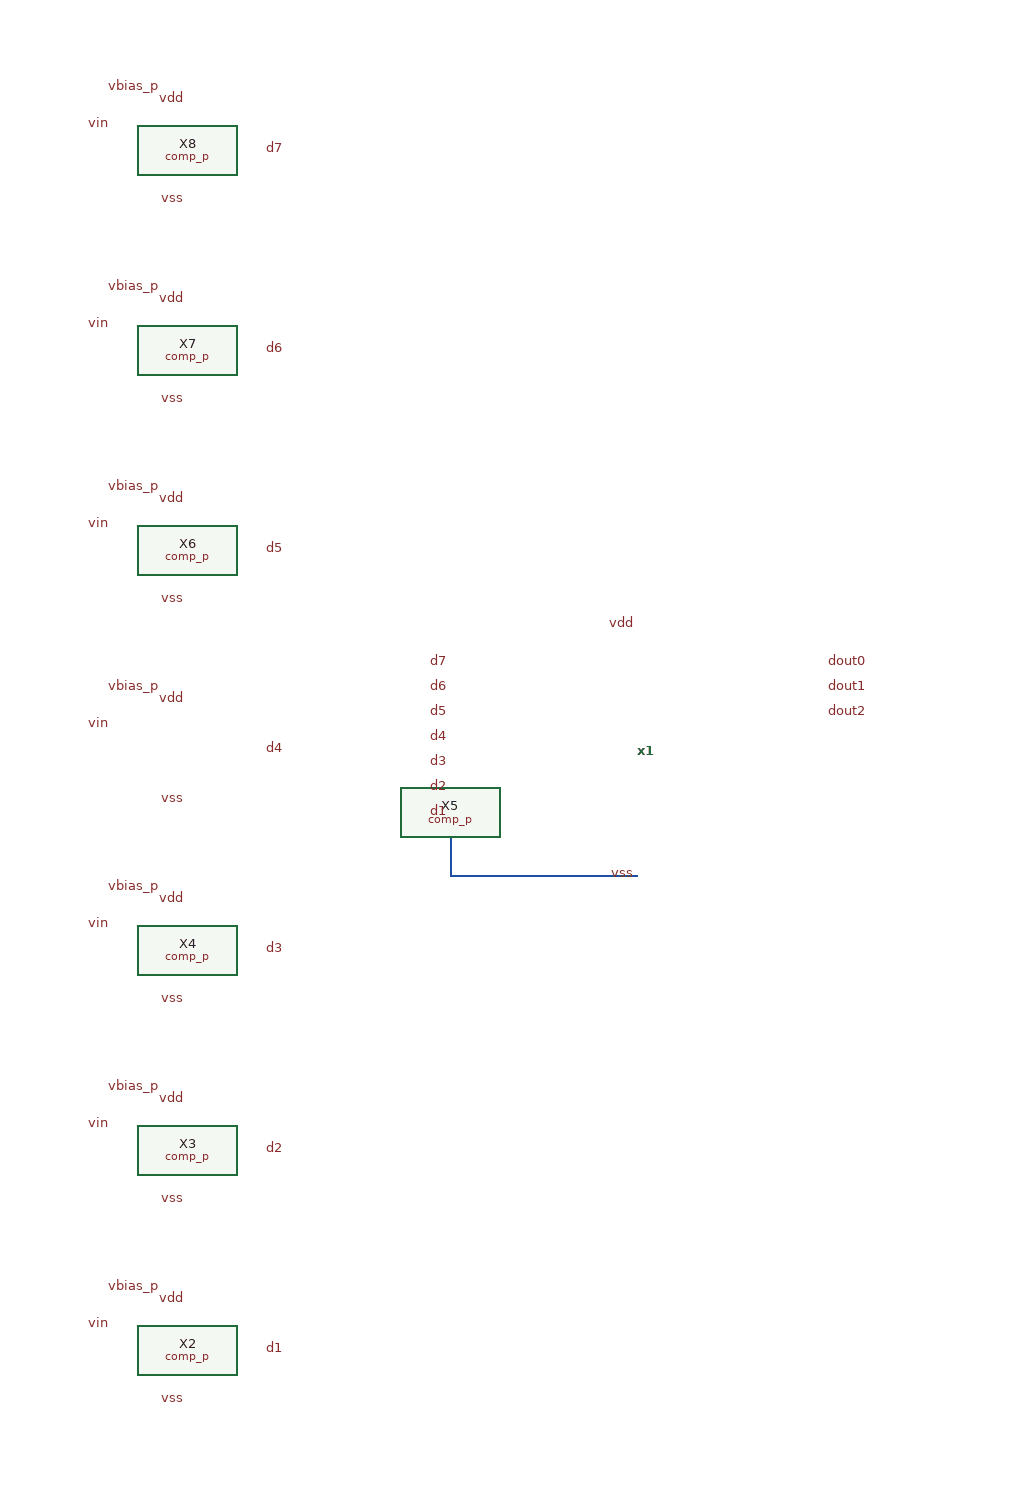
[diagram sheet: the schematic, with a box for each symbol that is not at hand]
v {xschem version=3.4.8RC file_version=1.3}
G {}
K {}
V {}
S {}
F {}
E {}
N 210 70 210 100 {lab=vss}
N 210 100 360 100 {lab=vss}
C {/home/bmott/ttsky25b_tiny_chaos/xsch/ip/encoder/encoder_3to8_.sym} 360 0 0 0 {name=x1}
C {/home/bmott/ttsky25b_tiny_chaos/xsch/ip/comparators/comp_p/comp_p.sym} 0 480 0 0 {name=X2}
C {devices/lab_pin.sym} 0 520 3 0 {name=p1 sig_type=std_logic lab=vss}
C {devices/lab_pin.sym} 0 440 1 0 {name=p2 sig_type=std_logic lab=vdd}
C {devices/lab_pin.sym} -60 460 0 0 {name=p3 sig_type=std_logic lab=vin}
C {devices/lab_pin.sym} 60 480 2 0 {name=p4 sig_type=std_logic lab=d1}
C {/home/bmott/ttsky25b_tiny_chaos/xsch/ip/comparators/comp_p/comp_p.sym} 0 320 0 0 {name=X3}
C {devices/lab_pin.sym} 0 360 3 0 {name=p5 sig_type=std_logic lab=vss}
C {devices/lab_pin.sym} 0 280 1 0 {name=p6 sig_type=std_logic lab=vdd}
C {devices/lab_pin.sym} -60 300 0 0 {name=p7 sig_type=std_logic lab=vin}
C {devices/lab_pin.sym} 60 320 2 0 {name=p8 sig_type=std_logic lab=d2}
C {/home/bmott/ttsky25b_tiny_chaos/xsch/ip/comparators/comp_p/comp_p.sym} 0 160 0 0 {name=X4}
C {devices/lab_pin.sym} 0 200 3 0 {name=p9 sig_type=std_logic lab=vss}
C {devices/lab_pin.sym} 0 120 1 0 {name=p10 sig_type=std_logic lab=vdd}
C {devices/lab_pin.sym} -60 140 0 0 {name=p11 sig_type=std_logic lab=vin}
C {devices/lab_pin.sym} 60 160 2 0 {name=p12 sig_type=std_logic lab=d3}
C {/home/bmott/ttsky25b_tiny_chaos/xsch/ip/comparators/comp_p/comp_p.sym} 0 0 0 0 {name=X5}
C {devices/lab_pin.sym} 0 40 3 0 {name=p13 sig_type=std_logic lab=vss}
C {devices/lab_pin.sym} 0 -40 1 0 {name=p14 sig_type=std_logic lab=vdd}
C {devices/lab_pin.sym} -60 -20 0 0 {name=p15 sig_type=std_logic lab=vin}
C {devices/lab_pin.sym} 60 0 2 0 {name=p16 sig_type=std_logic lab=d4}
C {/home/bmott/ttsky25b_tiny_chaos/xsch/ip/comparators/comp_p/comp_p.sym} 0 -160 0 0 {name=X6}
C {devices/lab_pin.sym} 0 -120 3 0 {name=p17 sig_type=std_logic lab=vss}
C {devices/lab_pin.sym} 0 -200 1 0 {name=p18 sig_type=std_logic lab=vdd}
C {devices/lab_pin.sym} -60 -180 0 0 {name=p19 sig_type=std_logic lab=vin}
C {devices/lab_pin.sym} 60 -160 2 0 {name=p20 sig_type=std_logic lab=d5}
C {/home/bmott/ttsky25b_tiny_chaos/xsch/ip/comparators/comp_p/comp_p.sym} 0 -320 0 0 {name=X7}
C {devices/lab_pin.sym} 0 -280 3 0 {name=p21 sig_type=std_logic lab=vss}
C {devices/lab_pin.sym} 0 -360 1 0 {name=p22 sig_type=std_logic lab=vdd}
C {devices/lab_pin.sym} -60 -340 0 0 {name=p23 sig_type=std_logic lab=vin}
C {devices/lab_pin.sym} 60 -320 2 0 {name=p24 sig_type=std_logic lab=d6}
C {/home/bmott/ttsky25b_tiny_chaos/xsch/ip/comparators/comp_p/comp_p.sym} 0 -480 0 0 {name=X8}
C {devices/lab_pin.sym} 0 -440 3 0 {name=p25 sig_type=std_logic lab=vss}
C {devices/lab_pin.sym} 0 -520 1 0 {name=p26 sig_type=std_logic lab=vdd}
C {devices/lab_pin.sym} -60 -500 0 0 {name=p27 sig_type=std_logic lab=vin}
C {devices/lab_pin.sym} 60 -480 2 0 {name=p28 sig_type=std_logic lab=d7}
C {devices/lab_pin.sym} 360 -100 1 0 {name=p33 sig_type=std_logic lab=vdd}
C {devices/lab_pin.sym} 360 100 3 0 {name=p34 sig_type=std_logic lab=vss}
C {devices/lab_pin.sym} -20 -50 1 0 {name=p29 sig_type=std_logic lab=vbias_p}
C {devices/lab_pin.sym} -20 110 1 0 {name=p30 sig_type=std_logic lab=vbias_p}
C {devices/lab_pin.sym} -20 270 1 0 {name=p31 sig_type=std_logic lab=vbias_p}
C {devices/lab_pin.sym} -20 430 1 0 {name=p32 sig_type=std_logic lab=vbias_p}
C {devices/lab_pin.sym} -20 -210 1 0 {name=p35 sig_type=std_logic lab=vbias_p}
C {devices/lab_pin.sym} -20 -370 1 0 {name=p36 sig_type=std_logic lab=vbias_p}
C {devices/lab_pin.sym} -20 -530 1 0 {name=p37 sig_type=std_logic lab=vbias_p}
C {devices/lab_pin.sym} 210 -70 0 0 {name=p38 sig_type=std_logic lab=d7}
C {devices/lab_pin.sym} 210 -50 0 0 {name=p39 sig_type=std_logic lab=d6}
C {devices/lab_pin.sym} 210 -30 0 0 {name=p40 sig_type=std_logic lab=d5}
C {devices/lab_pin.sym} 210 -10 0 0 {name=p41 sig_type=std_logic lab=d4}
C {devices/lab_pin.sym} 210 10 0 0 {name=p42 sig_type=std_logic lab=d3}
C {devices/lab_pin.sym} 210 30 0 0 {name=p43 sig_type=std_logic lab=d2}
C {devices/lab_pin.sym} 210 50 0 0 {name=p44 sig_type=std_logic lab=d1}
C {devices/lab_pin.sym} 510 -70 2 0 {name=p45 sig_type=std_logic lab=dout0}
C {devices/lab_pin.sym} 510 -50 2 0 {name=p46 sig_type=std_logic lab=dout1}
C {devices/lab_pin.sym} 510 -30 2 0 {name=p47 sig_type=std_logic lab=dout2}
